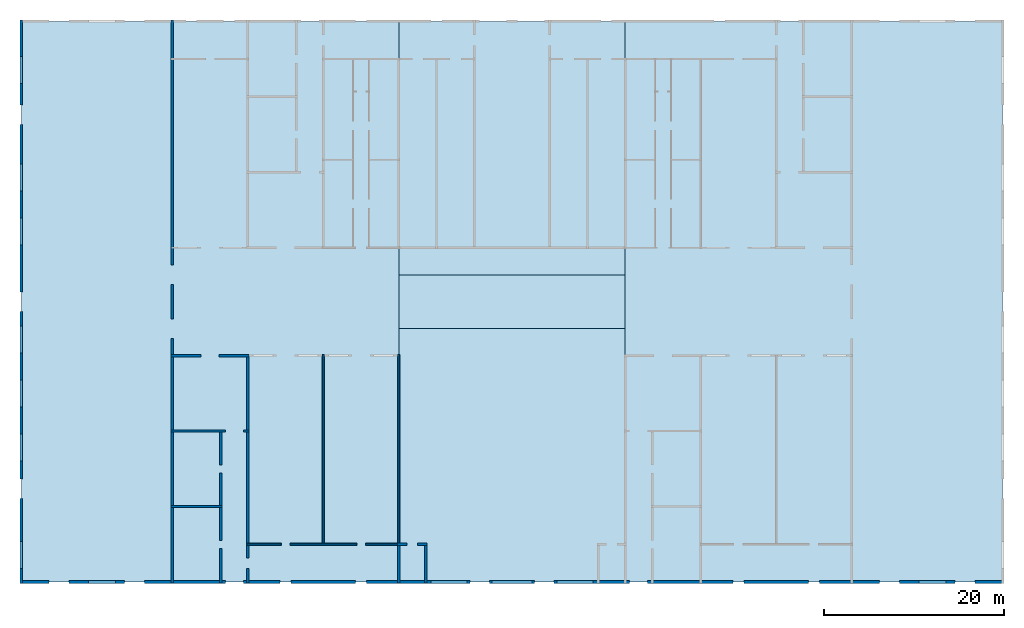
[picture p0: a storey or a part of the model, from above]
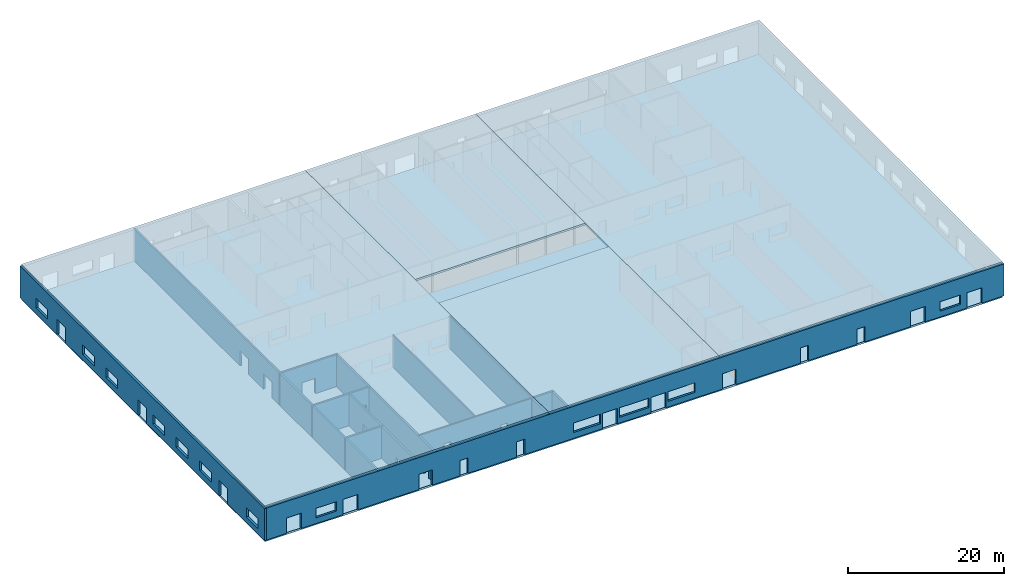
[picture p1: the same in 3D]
Properties of the parts of a building model (IFC4)

# File
Description: ViewDefinition[DesignTransferView]
File name: /dev/null
Time: 2026-10-29T19:12:21+03:00
Written by: IfcOpenShell 0.9.0.post1
Made in: IfcOpenShell 0.9.0.post1
Authorization: Nobody

# IfcBuildingStorey, Ground Floor
In: Sample Shopping Mall
Elevation: 0 mm

# IfcSpace (49)
In: Ground Floor
Name | LongName = Reference
01 | MALL STREET & ATRIUM
02 | LIFTS
03 | LIFTS
04 | ANCHOR STORE W
05 | ANCHOR STORE E
06 | SERVICE CORRIDOR SW1
07 | SERVICE CORRIDOR SE2
08 | SERVICE CORRIDOR NW1
09 | SERVICE CORRIDOR NW2
10 | SERVICE CORRIDOR NE3
11 | ESCAPE STAIR 1
12 | PASSAGE 1
13 | ELEC RISER 1
14 | MECH RISER 1
15 | SHOP 01
16 | SHOP 02
17 | ESCAPE STAIR 3
18 | PASSAGE 3
19 | ELEC RISER 3
20 | MECH RISER 3
21 | SHOP 03
22 | SHOP 04
23 | SHOP 05
24 | ESCAPE STAIR 2
25 | PASSAGE 2
26 | ELEC RISER 2
27 | MECH RISER 2
28 | LINK
29 | ACCESS WC
30 | MEN WC
31 | WOMEN WC
32 | BABY CARE
33 | FIRST AID
34 | MDB
35 | FIRE PUMP
36 | LOADING BAY
37 | AHU PLANT
38 | GEN SET
39 | LINK
40 | ACCESS WC
41 | MEN WC
42 | WOMEN WC
43 | BABY CARE
44 | FIRST AID
45 | SHOP 06
46 | ESCAPE STAIR 4
47 | PASSAGE 4
48 | ELEC RISER 4
49 | MECH RISER 4

# IfcDoor (127)
In: Ground Floor
OverallHeight: 2.4 mm; PredefinedType: DOOR
Name | OverallWidth (mm)
D01 | 1.2
D02 | 1.2
D03 | 1.1
20 x  | 1.1
D04 | 1.1
D05 | 1.1
D06 | 1.1
D07 | 1.1
D08 | 1.1
D09 | 1.1
D10 | 1.1
D11 | 1.1
D12 | 1.1
D13 | 1.1
D14 | 1.1
D15 | 1.1
D16 | 1.1
D17 | 1.1
D18 | 1.1
D19 | 1.1
D20 | 1.1
D21 | 1.1
D22 | 1.1
D23 | 1.2
D24 | 1.2
D25 | 1.2
D26 | 1.2
D27 | 1.2
D28 | 1.2
D29 | 1.2
D30 | 1.2
D31 | 1.2
D32 | 1.2
D33 | 1
34 x  | 1
D34 | 1
D35 | 1
8 x  | 0.9
9 x  | 1.2
D39 | 1
D41 | 1
D43 | 1
D44 | 1
D45 | 1
D48 | 1
D50 | 1
D52 | 1
D54 | 1
D55 | 1
D56 | 1
D60 | 1.2
D68 | 1.5
2 x  | 1.5
D69 | 1.5
D74 | 1.2
D80 | 1
D82 | 1
D83 | 1
D84 | 1

# IfcSlab (5)
In: Ground Floor
Name | PredefinedType
Ground slab | FLOOR
Roof slab 0 | ROOF
Roof slab 1 | ROOF
Roof slab 2 | ROOF
Roof slab 3 | ROOF

# IfcWall: WT-150 (10)
In: Ground Floor
Type - PredefinedType: SOLIDWALL
Pset_WallCommon - IsExternal: no; LoadBearing: no
Name
W21
W22
W23
W24
W27
W28
W43
W44
W57
W58

# IfcWall: WT-200 (14)
In: Ground Floor
Type - PredefinedType: SOLIDWALL
Pset_WallCommon - IsExternal: no; LoadBearing: yes
Name
W1
W4
W10
W12
W13
W15
W17
W29
W30
W33
W41
W46
W60
W61

# IfcWall: WT-250 (38)
In: Ground Floor
Type - PredefinedType: SOLIDWALL
Pset_WallCommon - LoadBearing: yes
Name | IsExternal
W2 | no
W3 | no
W5 | no
W6 | no
W7 | no
W8 | no
W9 | no
W11 | no
W14 | no
W16 | no
W18 | no
W19 | no
W20 | no
W25 | no
W26 | no
W31 | no
W32 | no
W36 | yes
W37 | no
W38 | no
W39 | no
W40 | no
W42 | no
W45 | no
W47 | no
W48 | no
W49 | no
W50 | no
W51 | no
W52 | no
W53 | no
W54 | no
W55 | no
W56 | no
W59 | no
W62 | no
W63 | no
W64 | yes

# IfcWall: WT-300 (4)
In: Ground Floor
Type - PredefinedType: SOLIDWALL
Pset_WallCommon - IsExternal: yes; LoadBearing: yes
Name
W0
W34
W35
W65

# IfcWindow (33)
In: Ground Floor
OverallHeight: 1.5 mm; PredefinedType: WINDOW
Name | OverallWidth (mm)
2 x  | 4
 | 4.4
12 x  | 2.2
18 x  | 3
